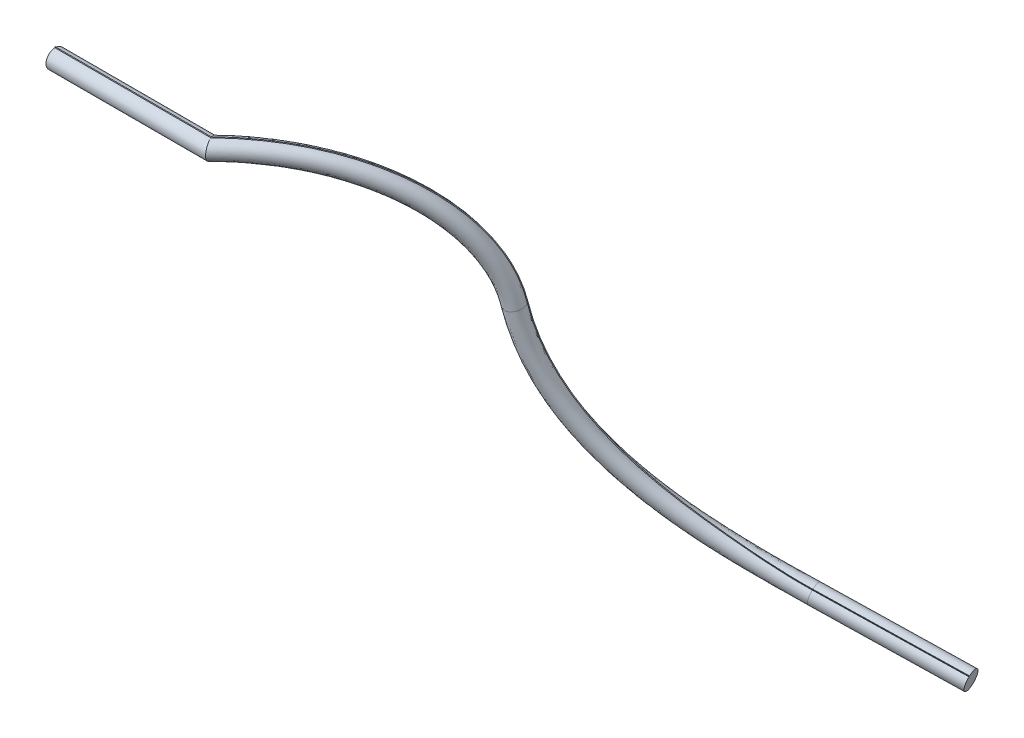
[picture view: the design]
ISO-10303-21;
HEADER;
FILE_DESCRIPTION(('STEP AP214'),'2;1');
FILE_NAME('part.step','',(''),(''),'','','');
FILE_SCHEMA(('AUTOMOTIVE_DESIGN { 1 0 10303 214 1 1 1 1 }'));
ENDSEC;
DATA;
#1=APPLICATION_CONTEXT('core data for automotive mechanical design processes');
#2=APPLICATION_PROTOCOL_DEFINITION('international standard','automotive_design',2000,#1);
#3=PRODUCT_CONTEXT('',#1,'mechanical');
#4=PRODUCT('Part','Part','',(#3));
#5=PRODUCT_RELATED_PRODUCT_CATEGORY('part','',(#4));
#6=PRODUCT_DEFINITION_FORMATION('','',#4);
#7=PRODUCT_DEFINITION_CONTEXT('part definition',#1,'design');
#8=PRODUCT_DEFINITION('design','',#6,#7);
#9=PRODUCT_DEFINITION_SHAPE('','',#8);
#10=(LENGTH_UNIT() NAMED_UNIT(*) SI_UNIT(.MILLI.,.METRE.));
#11=(NAMED_UNIT(*) PLANE_ANGLE_UNIT() SI_UNIT($,.RADIAN.));
#12=(NAMED_UNIT(*) SI_UNIT($,.STERADIAN.) SOLID_ANGLE_UNIT());
#13=UNCERTAINTY_MEASURE_WITH_UNIT(LENGTH_MEASURE(1.E-05),#10,'distance_accuracy_value','');
#14=(GEOMETRIC_REPRESENTATION_CONTEXT(3) GLOBAL_UNCERTAINTY_ASSIGNED_CONTEXT((#13)) GLOBAL_UNIT_ASSIGNED_CONTEXT((#10,
#11,#12)) REPRESENTATION_CONTEXT('',''));
#15=CARTESIAN_POINT('',(0.,0.,0.));
#16=DIRECTION('',(0.,0.,1.));
#17=DIRECTION('',(1.,0.,0.));
#18=AXIS2_PLACEMENT_3D('',#15,#16,#17);
#19=CARTESIAN_POINT('',(68.0766588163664,-45.6233046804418,-41.2127661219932));
#20=DIRECTION('',(0.937856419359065,-0.232670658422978,-0.257467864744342));
#21=DIRECTION('',(-0.264733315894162,0.,-0.964321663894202));
#22=AXIS2_PLACEMENT_3D('',#19,#20,#21);
#23=CYLINDRICAL_SURFACE('',#22,1.25);
#24=CARTESIAN_POINT('',(68.0766588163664,-45.6233046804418,-41.2127661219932));
#25=DIRECTION('',(0.937856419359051,-0.232670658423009,-0.257467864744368));
#26=DIRECTION('',(0.2926105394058,0.131350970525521,0.947167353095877));
#27=AXIS2_PLACEMENT_3D('',#24,#25,#26);
#28=CIRCLE('',#27,1.25);
#29=CARTESIAN_POINT('',(68.5024877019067,-44.6749516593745,-40.5186506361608));
#30=VERTEX_POINT('',#29);
#31=CARTESIAN_POINT('',(68.4945617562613,-44.6174497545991,-40.5994855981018));
#32=VERTEX_POINT('',#31);
#33=EDGE_CURVE('E217',#30,#32,#28,.T.);
#34=ORIENTED_EDGE('',*,*,#33,.T.);
#35=DIRECTION('',(0.937856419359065,-0.232670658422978,-0.257467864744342));
#36=VECTOR('',#35,1.);
#37=CARTESIAN_POINT('',(68.4945617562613,-44.6174497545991,-40.5994855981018));
#38=LINE('',#37,#36);
#39=CARTESIAN_POINT('',(85.0813365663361,-48.732424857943,-45.1530200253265));
#40=VERTEX_POINT('',#39);
#41=EDGE_CURVE('E64',#32,#40,#38,.T.);
#42=ORIENTED_EDGE('',*,*,#41,.T.);
#43=CARTESIAN_POINT('',(84.6634336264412,-49.7382797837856,-45.7663005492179));
#44=DIRECTION('',(0.937856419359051,-0.232670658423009,-0.257467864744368));
#45=DIRECTION('',(0.2926105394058,0.131350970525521,0.947167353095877));
#46=AXIS2_PLACEMENT_3D('',#43,#44,#45);
#47=CIRCLE('',#46,1.25);
#48=CARTESIAN_POINT('',(85.0892625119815,-48.7899267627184,-45.0721850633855));
#49=VERTEX_POINT('',#48);
#50=EDGE_CURVE('E72',#49,#40,#47,.T.);
#51=ORIENTED_EDGE('',*,*,#50,.F.);
#52=DIRECTION('',(0.937856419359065,-0.232670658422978,-0.257467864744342));
#53=VECTOR('',#52,1.);
#54=CARTESIAN_POINT('',(68.5024877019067,-44.6749516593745,-40.5186506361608));
#55=LINE('',#54,#53);
#56=EDGE_CURVE('E12',#30,#49,#55,.T.);
#57=ORIENTED_EDGE('',*,*,#56,.F.);
#58=EDGE_LOOP('',(#34,#42,#51,#57));
#59=FACE_BOUND('',#58,.T.);
#60=ADVANCED_FACE('F51',(#59),#23,.T.);
#61=CARTESIAN_POINT('',(68.5122101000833,-44.595538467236,-40.5550004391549));
#62=DIRECTION('',(0.0894631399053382,0.878961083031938,-0.468426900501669));
#63=DIRECTION('',(0.,0.470312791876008,0.882499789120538));
#64=AXIS2_PLACEMENT_3D('',#61,#62,#63);
#65=PLANE('',#64);
#66=DIRECTION('',(0.335293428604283,0.416283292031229,0.845154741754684));
#67=VECTOR('',#66,1.);
#68=CARTESIAN_POINT('',(68.5122101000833,-44.595538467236,-40.5550004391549));
#69=LINE('',#68,#67);
#70=CARTESIAN_POINT('',(68.5298584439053,-44.5736271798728,-40.5105152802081));
#71=VERTEX_POINT('',#70);
#72=EDGE_CURVE('E155',#32,#71,#69,.T.);
#73=ORIENTED_EDGE('',*,*,#72,.T.);
#74=DIRECTION('',(0.937856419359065,-0.232670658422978,-0.257467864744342));
#75=VECTOR('',#74,1.);
#76=CARTESIAN_POINT('',(68.5298584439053,-44.5736271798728,-40.5105152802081));
#77=LINE('',#76,#75);
#78=CARTESIAN_POINT('',(85.1166332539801,-48.6886022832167,-45.0640497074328));
#79=VERTEX_POINT('',#78);
#80=EDGE_CURVE('E169',#71,#79,#77,.T.);
#81=ORIENTED_EDGE('',*,*,#80,.T.);
#82=DIRECTION('',(0.335293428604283,0.416283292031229,0.845154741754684));
#83=VECTOR('',#82,1.);
#84=CARTESIAN_POINT('',(85.0989849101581,-48.7105135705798,-45.1085348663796));
#85=LINE('',#84,#83);
#86=EDGE_CURVE('E80',#40,#79,#85,.T.);
#87=ORIENTED_EDGE('',*,*,#86,.F.);
#88=ORIENTED_EDGE('',*,*,#41,.F.);
#89=EDGE_LOOP('',(#73,#81,#87,#88));
#90=FACE_BOUND('',#89,.T.);
#91=ADVANCED_FACE('F252',(#90),#65,.T.);
#92=CARTESIAN_POINT('',(68.5161730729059,-44.6242894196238,-40.5145829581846));
#93=DIRECTION('',(0.229834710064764,-0.139419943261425,0.963191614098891));
#94=DIRECTION('',(0.972691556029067,0.,-0.23210156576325));
#95=AXIS2_PLACEMENT_3D('',#92,#93,#94);
#96=PLANE('',#95);
#97=DIRECTION('',(-0.260002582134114,-0.962510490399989,-0.0772800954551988));
#98=VECTOR('',#97,1.);
#99=CARTESIAN_POINT('',(68.5161730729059,-44.6242894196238,-40.5145829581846));
#100=LINE('',#99,#98);
#101=EDGE_CURVE('E220',#71,#30,#100,.T.);
#102=ORIENTED_EDGE('',*,*,#101,.T.);
#103=ORIENTED_EDGE('',*,*,#56,.T.);
#104=DIRECTION('',(-0.260002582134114,-0.962510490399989,-0.0772800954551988));
#105=VECTOR('',#104,1.);
#106=CARTESIAN_POINT('',(85.1029478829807,-48.7392645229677,-45.0681173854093));
#107=LINE('',#106,#105);
#108=EDGE_CURVE('E173',#79,#49,#107,.T.);
#109=ORIENTED_EDGE('',*,*,#108,.F.);
#110=ORIENTED_EDGE('',*,*,#80,.F.);
#111=EDGE_LOOP('',(#102,#103,#109,#110));
#112=FACE_BOUND('',#111,.T.);
#113=ADVANCED_FACE('F224',(#112),#96,.T.);
#114=CARTESIAN_POINT('',(24.6211771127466,1.2490092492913,-6.86904668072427));
#115=DIRECTION('',(0.,-0.472669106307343,-0.881239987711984));
#116=DIRECTION('',(0.,0.881239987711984,-0.472669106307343));
#117=AXIS2_PLACEMENT_3D('',#114,#115,#116);
#118=PLANE('',#117);
#119=DIRECTION('',(0.187943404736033,-0.865536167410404,0.464246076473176));
#120=VECTOR('',#119,1.);
#121=CARTESIAN_POINT('',(21.1667914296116,0.666502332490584,-6.55660849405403));
#122=LINE('',#121,#120);
#123=CARTESIAN_POINT('',(21.0201613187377,1.34177829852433,-6.91880504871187));
#124=VERTEX_POINT('',#123);
#125=CARTESIAN_POINT('',(21.0403052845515,1.2490092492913,-6.86904668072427));
#126=VERTEX_POINT('',#125);
#127=EDGE_CURVE('E176',#124,#126,#122,.T.);
#128=ORIENTED_EDGE('',*,*,#127,.F.);
#129=DIRECTION('',(-1.,0.,0.));
#130=VECTOR('',#129,1.);
#131=CARTESIAN_POINT('',(24.6211771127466,1.34177829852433,-6.91880504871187));
#132=LINE('',#131,#130);
#133=CARTESIAN_POINT('',(0.,1.34177829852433,-6.91880504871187));
#134=VERTEX_POINT('',#133);
#135=EDGE_CURVE('E180',#124,#134,#132,.T.);
#136=ORIENTED_EDGE('',*,*,#135,.T.);
#137=DIRECTION('',(0.,-0.881239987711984,0.472669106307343));
#138=VECTOR('',#137,1.);
#139=CARTESIAN_POINT('',(0.,1.2490092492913,-6.86904668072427));
#140=LINE('',#139,#138);
#141=CARTESIAN_POINT('',(0.,1.2490092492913,-6.86904668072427));
#142=VERTEX_POINT('',#141);
#143=EDGE_CURVE('E184',#134,#142,#140,.T.);
#144=ORIENTED_EDGE('',*,*,#143,.T.);
#145=DIRECTION('',(-1.,0.,0.));
#146=VECTOR('',#145,1.);
#147=CARTESIAN_POINT('',(24.6211771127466,1.2490092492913,-6.86904668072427));
#148=LINE('',#147,#146);
#149=EDGE_CURVE('E182',#126,#142,#148,.T.);
#150=ORIENTED_EDGE('',*,*,#149,.F.);
#151=EDGE_LOOP('',(#128,#136,#144,#150));
#152=FACE_BOUND('',#151,.T.);
#153=ADVANCED_FACE('F231',(#152),#118,.F.);
#154=CARTESIAN_POINT('',(24.6211771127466,1.34177829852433,-6.91880504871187));
#155=DIRECTION('',(0.,-0.472669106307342,0.881239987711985));
#156=DIRECTION('',(0.,-0.881239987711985,-0.472669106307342));
#157=AXIS2_PLACEMENT_3D('',#154,#155,#156);
#158=PLANE('',#157);
#159=DIRECTION('',(0.187943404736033,0.865536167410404,0.464246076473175));
#160=VECTOR('',#159,1.);
#161=CARTESIAN_POINT('',(21.14735900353,1.92756207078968,-6.60460926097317));
#162=LINE('',#161,#160);
#163=CARTESIAN_POINT('',(21.0000173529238,1.2490092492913,-6.96856341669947));
#164=VERTEX_POINT('',#163);
#165=EDGE_CURVE('E179',#164,#124,#162,.T.);
#166=ORIENTED_EDGE('',*,*,#165,.F.);
#167=DIRECTION('',(-1.,0.,0.));
#168=VECTOR('',#167,1.);
#169=CARTESIAN_POINT('',(24.6211771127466,1.2490092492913,-6.96856341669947));
#170=LINE('',#169,#168);
#171=CARTESIAN_POINT('',(0.,1.2490092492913,-6.96856341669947));
#172=VERTEX_POINT('',#171);
#173=EDGE_CURVE('E177',#164,#172,#170,.T.);
#174=ORIENTED_EDGE('',*,*,#173,.T.);
#175=DIRECTION('',(0.,0.881239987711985,0.472669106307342));
#176=VECTOR('',#175,1.);
#177=CARTESIAN_POINT('',(0.,1.34177829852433,-6.91880504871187));
#178=LINE('',#177,#176);
#179=EDGE_CURVE('E187',#172,#134,#178,.T.);
#180=ORIENTED_EDGE('',*,*,#179,.T.);
#181=ORIENTED_EDGE('',*,*,#135,.F.);
#182=EDGE_LOOP('',(#166,#174,#180,#181));
#183=FACE_BOUND('',#182,.T.);
#184=ADVANCED_FACE('F234',(#183),#158,.F.);
#185=CARTESIAN_POINT('',(24.6211771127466,0.,-6.91880504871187));
#186=DIRECTION('',(-1.,0.,0.));
#187=DIRECTION('',(0.,0.,1.));
#188=AXIS2_PLACEMENT_3D('',#185,#186,#187);
#189=CYLINDRICAL_SURFACE('',#188,1.25);
#190=CARTESIAN_POINT('',(21.0201613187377,0.,-6.91880504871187));
#191=DIRECTION('',(0.926923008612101,0.,-0.375251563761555));
#192=DIRECTION('',(-0.375251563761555,0.,-0.926923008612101));
#193=AXIS2_PLACEMENT_3D('',#190,#191,#192);
#194=ELLIPSE('',#193,1.34854781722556,1.25);
#195=EDGE_CURVE('E128',#126,#164,#194,.T.);
#196=ORIENTED_EDGE('',*,*,#195,.F.);
#197=ORIENTED_EDGE('',*,*,#149,.T.);
#198=CARTESIAN_POINT('',(0.,0.,-6.91880504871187));
#199=DIRECTION('',(1.,0.,0.));
#200=DIRECTION('',(0.,0.,-1.));
#201=AXIS2_PLACEMENT_3D('',#198,#199,#200);
#202=CIRCLE('',#201,1.25);
#203=EDGE_CURVE('E190',#142,#172,#202,.T.);
#204=ORIENTED_EDGE('',*,*,#203,.T.);
#205=ORIENTED_EDGE('',*,*,#173,.F.);
#206=EDGE_LOOP('',(#196,#197,#204,#205));
#207=FACE_BOUND('',#206,.T.);
#208=ADVANCED_FACE('F241',(#207),#189,.T.);
#209=CARTESIAN_POINT('',(0.,0.,-6.91880504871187));
#210=DIRECTION('',(1.,0.,0.));
#211=DIRECTION('',(0.,0.,-1.));
#212=AXIS2_PLACEMENT_3D('',#209,#210,#211);
#213=PLANE('',#212);
#214=ORIENTED_EDGE('',*,*,#203,.F.);
#215=ORIENTED_EDGE('',*,*,#143,.F.);
#216=ORIENTED_EDGE('',*,*,#179,.F.);
#217=EDGE_LOOP('',(#214,#215,#216));
#218=FACE_BOUND('',#217,.T.);
#219=ADVANCED_FACE('F239',(#218),#213,.F.);
#220=CARTESIAN_POINT('',(21.0201613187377,1.34177829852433,-6.91880504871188));
#221=CARTESIAN_POINT('',(22.7025609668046,1.34177829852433,-8.54800962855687));
#222=CARTESIAN_POINT('',(26.0569241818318,0.958279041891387,-11.8136614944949));
#223=CARTESIAN_POINT('',(30.9730896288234,-0.80097450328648,-16.5732233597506));
#224=CARTESIAN_POINT('',(34.9737969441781,-3.43791542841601,-20.4272687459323));
#225=CARTESIAN_POINT('',(38.0175675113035,-6.51557415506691,-23.3243306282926));
#226=CARTESIAN_POINT('',(40.2018860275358,-9.58467143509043,-25.3726333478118));
#227=CARTESIAN_POINT('',(41.9527345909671,-13.2240571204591,-26.9549146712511));
#228=CARTESIAN_POINT('',(42.6964716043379,-15.9902305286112,-27.5800700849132));
#229=CARTESIAN_POINT('',(42.943133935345,-17.4066900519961,-27.7463292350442));
#230=CARTESIAN_POINT('',(21.026875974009,1.31085528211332,-6.90221892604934));
#231=CARTESIAN_POINT('',(22.7100324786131,1.31085528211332,-8.53215643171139));
#232=CARTESIAN_POINT('',(26.0663291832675,0.927783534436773,-11.799282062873));
#233=CARTESIAN_POINT('',(30.9771187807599,-0.830018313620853,-16.5533750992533));
#234=CARTESIAN_POINT('',(34.9747901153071,-3.46444486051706,-20.4041277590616));
#235=CARTESIAN_POINT('',(38.0153059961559,-6.53863378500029,-23.2977816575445));
#236=CARTESIAN_POINT('',(40.1969662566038,-9.60350261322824,-25.3432714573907));
#237=CARTESIAN_POINT('',(41.9453177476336,-13.2376482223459,-26.92304623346));
#238=CARTESIAN_POINT('',(42.6879414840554,-15.9976383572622,-27.5467896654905));
#239=CARTESIAN_POINT('',(42.9342675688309,-17.4121669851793,-27.7128221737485));
#240=CARTESIAN_POINT('',(21.0335906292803,1.27993226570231,-6.88563280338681));
#241=CARTESIAN_POINT('',(22.7175039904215,1.27993226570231,-8.51630323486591));
#242=CARTESIAN_POINT('',(26.0757341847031,0.897288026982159,-11.7849026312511));
#243=CARTESIAN_POINT('',(30.9811479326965,-0.859062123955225,-16.533526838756));
#244=CARTESIAN_POINT('',(34.9757832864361,-3.4909742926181,-20.3809867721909));
#245=CARTESIAN_POINT('',(38.0130444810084,-6.56169341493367,-23.2712326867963));
#246=CARTESIAN_POINT('',(40.1920464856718,-9.62233379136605,-25.3139095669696));
#247=CARTESIAN_POINT('',(41.9379009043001,-13.2512393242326,-26.891177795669));
#248=CARTESIAN_POINT('',(42.6794113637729,-16.0050461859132,-27.5135092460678));
#249=CARTESIAN_POINT('',(42.9254012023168,-17.4176439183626,-27.6793151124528));
#250=CARTESIAN_POINT('',(21.0403052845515,1.2490092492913,-6.86904668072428));
#251=CARTESIAN_POINT('',(22.7238069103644,1.2490092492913,-8.49931839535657));
#252=CARTESIAN_POINT('',(26.0856798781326,0.866789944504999,-11.7710466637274));
#253=CARTESIAN_POINT('',(30.9850270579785,-0.888096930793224,-16.5135337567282));
#254=CARTESIAN_POINT('',(34.9768036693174,-3.51753170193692,-20.3578707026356));
#255=CARTESIAN_POINT('',(38.0107680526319,-6.58469435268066,-23.2446722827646));
#256=CARTESIAN_POINT('',(40.1871673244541,-9.64139083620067,-25.2845754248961));
#257=CARTESIAN_POINT('',(41.9303355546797,-13.2639797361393,-26.8592091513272));
#258=CARTESIAN_POINT('',(42.6712013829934,-16.0142924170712,-27.4804446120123));
#259=CARTESIAN_POINT('',(42.9165348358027,-17.4231208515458,-27.645808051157));
#260=B_SPLINE_SURFACE_WITH_KNOTS('',3,3,((#220,#221,#222,#223,#224,#225,#226,#227,#228,#229),
(#230,#231,#232,#233,#234,#235,#236,#237,#238,#239),(#240,#241,#242,#243,#244,#245,#246,#247,
#248,#249),(#250,#251,#252,#253,#254,#255,#256,#257,#258,#259)),.UNSPECIFIED.,.F.,.F.,.F.,(4,4),
(4,1,1,1,1,1,1,4),(0.,0.0514443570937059),(0.,0.184817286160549,0.368761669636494,
0.554454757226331,0.664604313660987,0.775824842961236,0.887744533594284,1.),.UNSPECIFIED.);
#261=CARTESIAN_POINT('',(21.0403052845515,1.2490092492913,-6.86904668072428));
#262=CARTESIAN_POINT('',(22.7238069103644,1.2490092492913,-8.49931839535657));
#263=CARTESIAN_POINT('',(26.0856798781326,0.866789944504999,-11.7710466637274));
#264=CARTESIAN_POINT('',(30.9850270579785,-0.888096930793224,-16.5135337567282));
#265=CARTESIAN_POINT('',(34.9768036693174,-3.51753170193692,-20.3578707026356));
#266=CARTESIAN_POINT('',(38.0107680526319,-6.58469435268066,-23.2446722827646));
#267=CARTESIAN_POINT('',(40.1871673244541,-9.64139083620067,-25.2845754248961));
#268=CARTESIAN_POINT('',(41.9303355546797,-13.2639797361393,-26.8592091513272));
#269=CARTESIAN_POINT('',(42.6712013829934,-16.0142924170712,-27.4804446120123));
#270=CARTESIAN_POINT('',(42.9165348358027,-17.4231208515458,-27.645808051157));
#271=B_SPLINE_CURVE_WITH_KNOTS('',3,(#261,#262,#263,#264,#265,#266,#267,#268,#269,#270),
.UNSPECIFIED.,.F.,.F.,(4,1,1,1,1,1,1,4),(0.,0.184817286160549,0.368761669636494,
0.554454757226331,0.664604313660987,0.775824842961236,0.887744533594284,1.),.UNSPECIFIED.);
#272=CARTESIAN_POINT('',(42.9165348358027,-17.4231208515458,-27.645808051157));
#273=VERTEX_POINT('',#272);
#274=EDGE_CURVE('E151',#126,#273,#271,.T.);
#275=DIRECTION('',(-0.252672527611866,-0.156080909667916,0.954879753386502));
#276=VECTOR('',#275,1.);
#277=CARTESIAN_POINT('',(42.9298343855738,-17.4149054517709,-27.6960686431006));
#278=LINE('',#277,#276);
#279=CARTESIAN_POINT('',(42.943133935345,-17.4066900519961,-27.7463292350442));
#280=VERTEX_POINT('',#279);
#281=EDGE_CURVE('E193',#280,#273,#278,.T.);
#282=CARTESIAN_POINT('',(21.0201613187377,1.34177829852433,-6.91880504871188));
#283=CARTESIAN_POINT('',(22.7025609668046,1.34177829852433,-8.54800962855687));
#284=CARTESIAN_POINT('',(26.0569241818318,0.958279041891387,-11.8136614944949));
#285=CARTESIAN_POINT('',(30.9730896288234,-0.80097450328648,-16.5732233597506));
#286=CARTESIAN_POINT('',(34.9737969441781,-3.43791542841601,-20.4272687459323));
#287=CARTESIAN_POINT('',(38.0175675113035,-6.51557415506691,-23.3243306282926));
#288=CARTESIAN_POINT('',(40.2018860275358,-9.58467143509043,-25.3726333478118));
#289=CARTESIAN_POINT('',(41.9527345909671,-13.2240571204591,-26.9549146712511));
#290=CARTESIAN_POINT('',(42.6964716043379,-15.9902305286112,-27.5800700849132));
#291=CARTESIAN_POINT('',(42.943133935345,-17.4066900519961,-27.7463292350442));
#292=B_SPLINE_CURVE_WITH_KNOTS('',3,(#282,#283,#284,#285,#286,#287,#288,#289,#290,#291),
.UNSPECIFIED.,.F.,.F.,(4,1,1,1,1,1,1,4),(0.,0.184817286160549,0.368761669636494,
0.554454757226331,0.664604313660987,0.775824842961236,0.887744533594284,1.),.UNSPECIFIED.);
#293=EDGE_CURVE('E131',#124,#280,#292,.T.);
#294=ORIENTED_EDGE('',*,*,#127,.T.);
#295=ORIENTED_EDGE('',*,*,#274,.T.);
#296=ORIENTED_EDGE('',*,*,#281,.F.);
#297=ORIENTED_EDGE('',*,*,#293,.F.);
#298=EDGE_LOOP('',(#294,#295,#296,#297));
#299=FACE_BOUND('',#298,.T.);
#300=ADVANCED_FACE('F228',(#299),#260,.T.);
#301=CARTESIAN_POINT('',(21.0403052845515,1.2490092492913,-6.86904668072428));
#302=CARTESIAN_POINT('',(22.7238069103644,1.2490092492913,-8.49931839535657));
#303=CARTESIAN_POINT('',(26.0856798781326,0.866789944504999,-11.7710466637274));
#304=CARTESIAN_POINT('',(30.9850270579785,-0.888096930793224,-16.5135337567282));
#305=CARTESIAN_POINT('',(34.9768036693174,-3.51753170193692,-20.3578707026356));
#306=CARTESIAN_POINT('',(38.0107680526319,-6.58469435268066,-23.2446722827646));
#307=CARTESIAN_POINT('',(40.1871673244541,-9.64139083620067,-25.2845754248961));
#308=CARTESIAN_POINT('',(41.9303355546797,-13.2639797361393,-26.8592091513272));
#309=CARTESIAN_POINT('',(42.6712013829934,-16.0142924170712,-27.4804446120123));
#310=CARTESIAN_POINT('',(42.9165348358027,-17.4231208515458,-27.645808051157));
#311=CARTESIAN_POINT('',(22.0126774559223,1.15332198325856,-4.46715358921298));
#312=CARTESIAN_POINT('',(23.6925890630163,1.15332198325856,-6.09394879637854));
#313=CARTESIAN_POINT('',(28.0695093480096,0.794158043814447,-10.3474685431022));
#314=CARTESIAN_POINT('',(32.5488787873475,-0.941487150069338,-14.6827501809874));
#315=CARTESIAN_POINT('',(36.6381208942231,-3.5443383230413,-18.6209228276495));
#316=CARTESIAN_POINT('',(39.6531055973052,-6.58465082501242,-21.4892922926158));
#317=CARTESIAN_POINT('',(41.835449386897,-9.61951897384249,-23.5349039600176));
#318=CARTESIAN_POINT('',(43.5747682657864,-13.2001175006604,-25.1070141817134));
#319=CARTESIAN_POINT('',(44.3416265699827,-15.9605522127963,-25.752391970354));
#320=CARTESIAN_POINT('',(44.5812368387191,-17.3365152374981,-25.9138977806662));
#321=CARTESIAN_POINT('',(21.9933048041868,-1.25,-4.51500670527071));
#322=CARTESIAN_POINT('',(23.5807840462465,-1.25,-6.05229212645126));
#323=CARTESIAN_POINT('',(27.7601784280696,-1.58835182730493,-10.0835096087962));
#324=CARTESIAN_POINT('',(31.9599751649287,-3.21932242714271,-14.1274590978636));
#325=CARTESIAN_POINT('',(35.7752170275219,-5.63821340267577,-17.7725321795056));
#326=CARTESIAN_POINT('',(38.5384281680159,-8.41623451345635,-20.3768470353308));
#327=CARTESIAN_POINT('',(40.5079244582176,-11.1333022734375,-22.1970952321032));
#328=CARTESIAN_POINT('',(42.0468886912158,-14.2991364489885,-23.5686088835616));
#329=CARTESIAN_POINT('',(42.7201720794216,-16.6177443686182,-24.0945784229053));
#330=CARTESIAN_POINT('',(42.9297205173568,-17.8210771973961,-24.2358214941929));
#331=CARTESIAN_POINT('',(20.0470178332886,-1.25,-9.32260339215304));
#332=CARTESIAN_POINT('',(21.6173209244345,-1.25,-10.843255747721));
#333=CARTESIAN_POINT('',(23.7757576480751,-1.63287811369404,-12.9172643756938));
#334=CARTESIAN_POINT('',(28.7831743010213,-3.29366955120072,-17.7426881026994));
#335=CARTESIAN_POINT('',(32.3843329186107,-5.75212472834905,-21.1792787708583));
#336=CARTESIAN_POINT('',(35.1646350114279,-8.56050957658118,-23.7987630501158));
#337=CARTESIAN_POINT('',(37.1067812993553,-11.303973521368,-25.5906771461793));
#338=CARTESIAN_POINT('',(38.6321656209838,-14.4903222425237,-26.9476685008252));
#339=CARTESIAN_POINT('',(39.2592583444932,-16.8295359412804,-27.4247745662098));
#340=CARTESIAN_POINT('',(39.4688076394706,-18.0328736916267,-27.5660182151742));
#341=CARTESIAN_POINT('',(20.027645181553,1.15332198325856,-9.37045650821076));
#342=CARTESIAN_POINT('',(21.6732044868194,1.15332198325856,-10.9639855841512));
#343=CARTESIAN_POINT('',(24.0135520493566,0.748745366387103,-13.2451721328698));
#344=CARTESIAN_POINT('',(29.3066977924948,-1.01731434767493,-18.3678775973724));
#345=CARTESIAN_POINT('',(33.1800552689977,-3.66051724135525,-22.0958001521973));
#346=CARTESIAN_POINT('',(36.2120817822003,-6.73179816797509,-24.9792639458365));
#347=CARTESIAN_POINT('',(38.3666169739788,-9.79358723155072,-26.9960606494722));
#348=CARTESIAN_POINT('',(40.0920624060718,-13.3951115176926,-28.5533368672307));
#349=CARTESIAN_POINT('',(40.8118145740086,-16.1765551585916,-29.1488827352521));
#350=CARTESIAN_POINT('',(41.0514265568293,-17.5525280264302,-29.3103897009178));
#351=CARTESIAN_POINT('',(21.0000173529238,1.2490092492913,-6.96856341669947));
#352=CARTESIAN_POINT('',(22.6739047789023,1.2490092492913,-8.58952491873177));
#353=CARTESIAN_POINT('',(26.0074830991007,0.865868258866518,-11.8338500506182));
#354=CARTESIAN_POINT('',(30.9180913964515,-0.889635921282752,-16.5872295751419));
#355=CARTESIAN_POINT('',(34.906789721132,-3.51988961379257,-20.4285613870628));
#356=CARTESIAN_POINT('',(37.9408937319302,-6.58768091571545,-23.3154695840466));
#357=CARTESIAN_POINT('',(40.1167740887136,-9.64492338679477,-25.3548319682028));
#358=CARTESIAN_POINT('',(41.8596484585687,-13.267938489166,-26.9291526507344));
#359=CARTESIAN_POINT('',(42.5995603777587,-16.0186738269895,-27.5493790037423));
#360=CARTESIAN_POINT('',(42.8448943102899,-17.4275050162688,-27.7147427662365));
#361=(BOUNDED_SURFACE() B_SPLINE_SURFACE(3,3,((#301,#302,#303,#304,#305,#306,#307,#308,#309,
#310),(#311,#312,#313,#314,#315,#316,#317,#318,#319,#320),(#321,#322,#323,#324,#325,#326,#327,
#328,#329,#330),(#331,#332,#333,#334,#335,#336,#337,#338,#339,#340),(#341,#342,#343,#344,#345,
#346,#347,#348,#349,#350),(#351,#352,#353,#354,#355,#356,#357,#358,#359,#360)),.UNSPECIFIED.,
.F.,.F.,.F.) B_SPLINE_SURFACE_WITH_KNOTS((4,2,4),(4,1,1,1,1,1,1,4),(0.0514443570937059,0.5,
0.948555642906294),(0.,0.184817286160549,0.368761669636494,0.554454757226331,0.664604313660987,
0.775824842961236,0.887744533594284,1.),
.UNSPECIFIED.) GEOMETRIC_REPRESENTATION_ITEM() RATIONAL_B_SPLINE_SURFACE(((1.,1.,1.,1.,1.,1.,1.,
1.,1.,1.),(0.120134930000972,0.120134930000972,0.120134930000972,0.120134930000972,
0.120134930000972,0.120134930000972,0.120134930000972,0.120134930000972,0.120134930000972,
0.120134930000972),(0.0416393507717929,0.0416393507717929,0.0416393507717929,0.0416393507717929,
0.0416393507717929,0.0416393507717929,0.0416393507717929,0.0416393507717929,0.0416393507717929,
0.0416393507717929),(0.0416393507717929,0.0416393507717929,0.0416393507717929,
0.0416393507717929,0.0416393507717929,0.0416393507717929,0.0416393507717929,0.0416393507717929,
0.0416393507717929,0.0416393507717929),(0.120134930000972,0.120134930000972,0.120134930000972,
0.120134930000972,0.120134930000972,0.120134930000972,0.120134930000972,0.120134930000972,
0.120134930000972,0.120134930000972),(1.,1.,1.,1.,1.,1.,1.,1.,1.,1.))) REPRESENTATION_ITEM('') SURFACE());
#362=CARTESIAN_POINT('',(21.0000173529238,1.2490092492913,-6.96856341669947));
#363=CARTESIAN_POINT('',(22.6739047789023,1.2490092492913,-8.58952491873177));
#364=CARTESIAN_POINT('',(26.0074830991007,0.865868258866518,-11.8338500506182));
#365=CARTESIAN_POINT('',(30.9180913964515,-0.889635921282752,-16.5872295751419));
#366=CARTESIAN_POINT('',(34.906789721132,-3.51988961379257,-20.4285613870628));
#367=CARTESIAN_POINT('',(37.9408937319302,-6.58768091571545,-23.3154695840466));
#368=CARTESIAN_POINT('',(40.1167740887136,-9.64492338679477,-25.3548319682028));
#369=CARTESIAN_POINT('',(41.8596484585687,-13.267938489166,-26.9291526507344));
#370=CARTESIAN_POINT('',(42.5995603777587,-16.0186738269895,-27.5493790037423));
#371=CARTESIAN_POINT('',(42.8448943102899,-17.4275050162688,-27.7147427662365));
#372=B_SPLINE_CURVE_WITH_KNOTS('',3,(#362,#363,#364,#365,#366,#367,#368,#369,#370,#371),
.UNSPECIFIED.,.F.,.F.,(4,1,1,1,1,1,1,4),(0.,0.184817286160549,0.368761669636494,
0.554454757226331,0.664604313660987,0.775824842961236,0.887744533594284,1.),.UNSPECIFIED.);
#373=CARTESIAN_POINT('',(42.8448943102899,-17.4275050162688,-27.7147427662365));
#374=VERTEX_POINT('',#373);
#375=EDGE_CURVE('E120',#164,#374,#372,.T.);
#376=CARTESIAN_POINT('',(42.0403226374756,-17.6760447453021,-26.7909503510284));
#377=DIRECTION('',(0.170422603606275,-0.97865255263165,-0.114870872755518));
#378=DIRECTION('',(0.985173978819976,0.171558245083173,0.));
#379=AXIS2_PLACEMENT_3D('',#376,#377,#378);
#380=CIRCLE('',#379,1.25);
#381=EDGE_CURVE('E125',#273,#374,#380,.T.);
#382=ORIENTED_EDGE('',*,*,#195,.T.);
#383=ORIENTED_EDGE('',*,*,#375,.T.);
#384=ORIENTED_EDGE('',*,*,#381,.F.);
#385=ORIENTED_EDGE('',*,*,#274,.F.);
#386=EDGE_LOOP('',(#382,#383,#384,#385));
#387=FACE_BOUND('',#386,.T.);
#388=ADVANCED_FACE('F122',(#387),#361,.T.);
#389=CARTESIAN_POINT('',(21.0000173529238,1.2490092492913,-6.96856341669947));
#390=CARTESIAN_POINT('',(22.6739047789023,1.2490092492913,-8.58952491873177));
#391=CARTESIAN_POINT('',(26.0074830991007,0.865868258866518,-11.8338500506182));
#392=CARTESIAN_POINT('',(30.9180913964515,-0.889635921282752,-16.5872295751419));
#393=CARTESIAN_POINT('',(34.906789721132,-3.51988961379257,-20.4285613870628));
#394=CARTESIAN_POINT('',(37.9408937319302,-6.58768091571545,-23.3154695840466));
#395=CARTESIAN_POINT('',(40.1167740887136,-9.64492338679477,-25.3548319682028));
#396=CARTESIAN_POINT('',(41.8596484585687,-13.267938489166,-26.9291526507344));
#397=CARTESIAN_POINT('',(42.5995603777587,-16.0186738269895,-27.5493790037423));
#398=CARTESIAN_POINT('',(42.8448943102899,-17.4275050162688,-27.7147427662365));
#399=CARTESIAN_POINT('',(21.0067320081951,1.27993226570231,-6.95197729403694));
#400=CARTESIAN_POINT('',(22.6838683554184,1.27993226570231,-8.57608499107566));
#401=CARTESIAN_POINT('',(26.0237729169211,0.896673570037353,-11.8269361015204));
#402=CARTESIAN_POINT('',(30.936477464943,-0.860088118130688,-16.5826121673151));
#403=CARTESIAN_POINT('',(34.9291143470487,-3.49254623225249,-20.4281206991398));
#404=CARTESIAN_POINT('',(37.966460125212,-6.56368446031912,-23.3184294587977));
#405=CARTESIAN_POINT('',(40.1451180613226,-9.62468881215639,-25.3607476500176));
#406=CARTESIAN_POINT('',(41.8907760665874,-13.2538785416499,-26.9378066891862));
#407=CARTESIAN_POINT('',(42.6316506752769,-16.0079670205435,-27.5594654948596));
#408=CARTESIAN_POINT('',(42.8776408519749,-17.4205666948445,-27.7252715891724));
#409=CARTESIAN_POINT('',(21.0134466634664,1.31085528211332,-6.93539117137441));
#410=CARTESIAN_POINT('',(22.6932146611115,1.31085528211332,-8.56204730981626));
#411=CARTESIAN_POINT('',(26.0403485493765,0.92747630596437,-11.8202987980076));
#412=CARTESIAN_POINT('',(30.9547835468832,-0.830531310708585,-16.5779177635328));
#413=CARTESIAN_POINT('',(34.9514556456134,-3.46523083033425,-20.427694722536));
#414=CARTESIAN_POINT('',(37.9920138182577,-6.53962930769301,-23.3213800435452));
#415=CARTESIAN_POINT('',(40.1735020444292,-9.60468012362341,-25.3666904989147));
#416=CARTESIAN_POINT('',(41.9217553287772,-13.2389678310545,-26.9463606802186));
#417=CARTESIAN_POINT('',(42.6640611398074,-15.9990987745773,-27.5697677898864));
#418=CARTESIAN_POINT('',(42.91038739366,-17.4136283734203,-27.7358004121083));
#419=CARTESIAN_POINT('',(21.0201613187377,1.34177829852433,-6.91880504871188));
#420=CARTESIAN_POINT('',(22.7025609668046,1.34177829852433,-8.54800962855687));
#421=CARTESIAN_POINT('',(26.0569241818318,0.958279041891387,-11.8136614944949));
#422=CARTESIAN_POINT('',(30.9730896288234,-0.80097450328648,-16.5732233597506));
#423=CARTESIAN_POINT('',(34.9737969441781,-3.43791542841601,-20.4272687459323));
#424=CARTESIAN_POINT('',(38.0175675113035,-6.51557415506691,-23.3243306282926));
#425=CARTESIAN_POINT('',(40.2018860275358,-9.58467143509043,-25.3726333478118));
#426=CARTESIAN_POINT('',(41.9527345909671,-13.2240571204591,-26.9549146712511));
#427=CARTESIAN_POINT('',(42.6964716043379,-15.9902305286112,-27.5800700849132));
#428=CARTESIAN_POINT('',(42.943133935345,-17.4066900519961,-27.7463292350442));
#429=B_SPLINE_SURFACE_WITH_KNOTS('',3,3,((#389,#390,#391,#392,#393,#394,#395,#396,#397,#398),
(#399,#400,#401,#402,#403,#404,#405,#406,#407,#408),(#409,#410,#411,#412,#413,#414,#415,#416,
#417,#418),(#419,#420,#421,#422,#423,#424,#425,#426,#427,#428)),.UNSPECIFIED.,.F.,.F.,.F.,(4,4),
(4,1,1,1,1,1,1,4),(0.948555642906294,1.),(0.,0.184817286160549,0.368761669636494,
0.554454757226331,0.664604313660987,0.775824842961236,0.887744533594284,1.),.UNSPECIFIED.);
#430=DIRECTION('',(0.933206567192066,0.197727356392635,-0.300048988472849));
#431=VECTOR('',#430,1.);
#432=CARTESIAN_POINT('',(42.8940141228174,-17.4170975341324,-27.7305360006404));
#433=LINE('',#432,#431);
#434=EDGE_CURVE('E134',#374,#280,#433,.T.);
#435=ORIENTED_EDGE('',*,*,#165,.T.);
#436=ORIENTED_EDGE('',*,*,#293,.T.);
#437=ORIENTED_EDGE('',*,*,#434,.F.);
#438=ORIENTED_EDGE('',*,*,#375,.F.);
#439=EDGE_LOOP('',(#435,#436,#437,#438));
#440=FACE_BOUND('',#439,.T.);
#441=ADVANCED_FACE('F135',(#440),#429,.T.);
#442=CARTESIAN_POINT('',(84.2412330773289,-50.7161588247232,-46.4205170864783));
#443=DIRECTION('',(-0.937856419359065,0.232670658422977,0.257467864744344));
#444=DIRECTION('',(-0.292610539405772,-0.131350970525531,-0.947167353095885));
#445=AXIS2_PLACEMENT_3D('',#442,#443,#444);
#446=PLANE('',#445);
#447=ORIENTED_EDGE('',*,*,#108,.T.);
#448=ORIENTED_EDGE('',*,*,#50,.T.);
#449=ORIENTED_EDGE('',*,*,#86,.T.);
#450=EDGE_LOOP('',(#447,#448,#449));
#451=FACE_BOUND('',#450,.T.);
#452=ADVANCED_FACE('F261',(#451),#446,.F.);
#453=CARTESIAN_POINT('',(42.8448943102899,-17.4275050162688,-27.7147427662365));
#454=CARTESIAN_POINT('',(43.2873461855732,-19.9682868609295,-28.0129710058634));
#455=CARTESIAN_POINT('',(44.2973765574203,-23.2368966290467,-28.682958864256));
#456=CARTESIAN_POINT('',(45.7259938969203,-26.2309724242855,-29.6412649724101));
#457=CARTESIAN_POINT('',(46.8662104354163,-28.4057189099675,-30.4013978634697));
#458=CARTESIAN_POINT('',(47.7258276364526,-29.7900990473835,-30.9682862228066));
#459=CARTESIAN_POINT('',(48.6838432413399,-31.1071226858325,-31.5754811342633));
#460=CARTESIAN_POINT('',(49.6559609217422,-32.4407978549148,-32.1913146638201));
#461=CARTESIAN_POINT('',(50.7141930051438,-33.6868229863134,-32.8393190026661));
#462=CARTESIAN_POINT('',(52.3779065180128,-35.3887842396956,-33.8105674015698));
#463=CARTESIAN_POINT('',(53.5369739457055,-36.4976580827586,-34.4731939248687));
#464=CARTESIAN_POINT('',(54.7698546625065,-37.5241346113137,-35.142449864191));
#465=CARTESIAN_POINT('',(56.7006367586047,-39.0248507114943,-36.1556499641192));
#466=CARTESIAN_POINT('',(58.0527472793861,-39.9422104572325,-36.8223845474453));
#467=CARTESIAN_POINT('',(59.7866353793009,-40.9731147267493,-37.5892913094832));
#468=CARTESIAN_POINT('',(62.6039382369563,-42.5971961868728,-38.805152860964));
#469=CARTESIAN_POINT('',(65.6029482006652,-43.9000759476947,-39.8056566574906));
#470=CARTESIAN_POINT('',(68.4945617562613,-44.6174497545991,-40.5994855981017));
#471=CARTESIAN_POINT('',(42.8776408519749,-17.4205666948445,-27.7252715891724));
#472=CARTESIAN_POINT('',(43.3193395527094,-19.9570234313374,-28.022992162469));
#473=CARTESIAN_POINT('',(44.328794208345,-23.2231733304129,-28.6911694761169));
#474=CARTESIAN_POINT('',(45.7563413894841,-26.2144748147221,-29.647316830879));
#475=CARTESIAN_POINT('',(46.89570641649,-28.3871987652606,-30.4057256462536));
#476=CARTESIAN_POINT('',(47.7546849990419,-29.770288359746,-30.9713131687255));
#477=CARTESIAN_POINT('',(48.7120983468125,-31.0863652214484,-31.5769396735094));
#478=CARTESIAN_POINT('',(49.683606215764,-32.4190856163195,-32.1911802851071));
#479=CARTESIAN_POINT('',(50.7412717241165,-33.6645109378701,-32.8373462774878));
#480=CARTESIAN_POINT('',(52.4040713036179,-35.3659397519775,-33.8056108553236));
#481=CARTESIAN_POINT('',(53.5624967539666,-36.4745690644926,-34.4661359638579));
#482=CARTESIAN_POINT('',(54.7946431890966,-37.5009919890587,-35.133155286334));
#483=CARTESIAN_POINT('',(56.7242129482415,-39.0018921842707,-36.142866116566));
#484=CARTESIAN_POINT('',(58.0754041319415,-39.9197090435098,-36.807191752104));
#485=CARTESIAN_POINT('',(59.8079310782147,-40.9519427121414,-37.5710228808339));
#486=CARTESIAN_POINT('',(62.6229529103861,-42.5784635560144,-38.7818894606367));
#487=CARTESIAN_POINT('',(65.6189140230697,-43.8865104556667,-39.7771529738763));
#488=CARTESIAN_POINT('',(68.5063273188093,-44.6028422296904,-40.5698288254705));
#489=CARTESIAN_POINT('',(42.91038739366,-17.4136283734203,-27.7358004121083));
#490=CARTESIAN_POINT('',(43.3517074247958,-19.9479105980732,-28.0332657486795));
#491=CARTESIAN_POINT('',(44.3602084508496,-23.2094897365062,-28.6993821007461));
#492=CARTESIAN_POINT('',(45.7866480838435,-26.197702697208,-29.6533382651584));
#493=CARTESIAN_POINT('',(46.9251644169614,-28.3683618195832,-30.4100206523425));
#494=CARTESIAN_POINT('',(47.7835463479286,-29.7503833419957,-30.9743342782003));
#495=CARTESIAN_POINT('',(48.7403533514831,-31.0656103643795,-31.5783983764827));
#496=CARTESIAN_POINT('',(49.7112466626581,-32.3974725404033,-32.1910518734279));
#497=CARTESIAN_POINT('',(50.7682961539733,-33.6422693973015,-32.8353647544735));
#498=CARTESIAN_POINT('',(52.4301862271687,-35.3431168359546,-33.8006430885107));
#499=CARTESIAN_POINT('',(53.5879978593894,-36.4514664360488,-34.4590714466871));
#500=CARTESIAN_POINT('',(54.8195372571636,-37.4778535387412,-35.123888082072));
#501=CARTESIAN_POINT('',(56.7480668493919,-38.9789734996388,-36.1301563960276));
#502=CARTESIAN_POINT('',(58.0984250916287,-39.897281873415,-36.7920977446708));
#503=CARTESIAN_POINT('',(59.8293643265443,-40.9308009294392,-37.5527919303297));
#504=CARTESIAN_POINT('',(62.6416105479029,-42.5596566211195,-38.7585290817));
#505=CARTESIAN_POINT('',(65.6327192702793,-43.87240895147,-39.7480561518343));
#506=CARTESIAN_POINT('',(68.5180928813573,-44.5882347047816,-40.5401720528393));
#507=CARTESIAN_POINT('',(42.943133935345,-17.4066900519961,-27.7463292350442));
#508=CARTESIAN_POINT('',(43.3840752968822,-19.9387977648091,-28.0435393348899));
#509=CARTESIAN_POINT('',(44.3916226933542,-23.1958061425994,-28.7075947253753));
#510=CARTESIAN_POINT('',(45.8169547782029,-26.1809305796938,-29.6593596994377));
#511=CARTESIAN_POINT('',(46.9546224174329,-28.3495248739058,-30.4143156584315));
#512=CARTESIAN_POINT('',(47.8124076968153,-29.7304783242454,-30.9773553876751));
#513=CARTESIAN_POINT('',(48.7686083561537,-31.0448555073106,-31.5798570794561));
#514=CARTESIAN_POINT('',(49.7388871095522,-32.3758594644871,-32.1909234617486));
#515=CARTESIAN_POINT('',(50.79532058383,-33.6200278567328,-32.8333832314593));
#516=CARTESIAN_POINT('',(52.4563011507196,-35.3202939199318,-33.7956753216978));
#517=CARTESIAN_POINT('',(53.6134989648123,-36.4283638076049,-34.4520069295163));
#518=CARTESIAN_POINT('',(54.8444313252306,-37.4547150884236,-35.11462087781));
#519=CARTESIAN_POINT('',(56.7719207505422,-38.956054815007,-36.1174466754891));
#520=CARTESIAN_POINT('',(58.1214460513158,-39.8748547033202,-36.7770037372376));
#521=CARTESIAN_POINT('',(59.850797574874,-40.9096591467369,-37.5345609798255));
#522=CARTESIAN_POINT('',(62.6602681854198,-42.5408496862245,-38.7351687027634));
#523=CARTESIAN_POINT('',(65.6465245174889,-43.8583074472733,-39.7189593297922));
#524=CARTESIAN_POINT('',(68.5298584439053,-44.5736271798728,-40.510515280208));
#525=B_SPLINE_SURFACE_WITH_KNOTS('',3,3,((#453,#454,#455,#456,#457,#458,#459,#460,#461,#462,
#463,#464,#465,#466,#467,#468,#469,#470),(#471,#472,#473,#474,#475,#476,#477,#478,#479,#480,
#481,#482,#483,#484,#485,#486,#487,#488),(#489,#490,#491,#492,#493,#494,#495,#496,#497,#498,
#499,#500,#501,#502,#503,#504,#505,#506),(#507,#508,#509,#510,#511,#512,#513,#514,#515,#516,
#517,#518,#519,#520,#521,#522,#523,#524)),.UNSPECIFIED.,.F.,.F.,.F.,(4,4),(4,1,2,1,2,2,1,2,2,1,
4),(0.94582657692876,1.),(0.,0.186666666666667,0.25,0.373333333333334,0.375,0.5,0.56,0.625,0.75,
0.78,1.),.UNSPECIFIED.);
#526=CARTESIAN_POINT('',(42.943133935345,-17.4066900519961,-27.7463292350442));
#527=CARTESIAN_POINT('',(43.3840752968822,-19.9387977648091,-28.0435393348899));
#528=CARTESIAN_POINT('',(44.3916226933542,-23.1958061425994,-28.7075947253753));
#529=CARTESIAN_POINT('',(45.8169547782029,-26.1809305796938,-29.6593596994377));
#530=CARTESIAN_POINT('',(46.9546224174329,-28.3495248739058,-30.4143156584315));
#531=CARTESIAN_POINT('',(47.8124076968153,-29.7304783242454,-30.9773553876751));
#532=CARTESIAN_POINT('',(48.7686083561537,-31.0448555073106,-31.5798570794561));
#533=CARTESIAN_POINT('',(49.7388871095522,-32.3758594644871,-32.1909234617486));
#534=CARTESIAN_POINT('',(50.79532058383,-33.6200278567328,-32.8333832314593));
#535=CARTESIAN_POINT('',(52.4563011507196,-35.3202939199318,-33.7956753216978));
#536=CARTESIAN_POINT('',(53.6134989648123,-36.4283638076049,-34.4520069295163));
#537=CARTESIAN_POINT('',(54.8444313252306,-37.4547150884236,-35.11462087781));
#538=CARTESIAN_POINT('',(56.7719207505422,-38.956054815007,-36.1174466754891));
#539=CARTESIAN_POINT('',(58.1214460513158,-39.8748547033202,-36.7770037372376));
#540=CARTESIAN_POINT('',(59.850797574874,-40.9096591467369,-37.5345609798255));
#541=CARTESIAN_POINT('',(62.6602681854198,-42.5408496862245,-38.7351687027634));
#542=CARTESIAN_POINT('',(65.6465245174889,-43.8583074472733,-39.7189593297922));
#543=CARTESIAN_POINT('',(68.5298584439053,-44.5736271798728,-40.510515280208));
#544=B_SPLINE_CURVE_WITH_KNOTS('',3,(#526,#527,#528,#529,#530,#531,#532,#533,#534,#535,#536,
#537,#538,#539,#540,#541,#542,#543),.UNSPECIFIED.,.F.,.F.,(4,1,2,1,2,2,1,2,2,1,4),(0.,
0.186666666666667,0.25,0.373333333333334,0.375,0.5,0.56,0.625,0.75,0.78,1.),.UNSPECIFIED.);
#545=EDGE_CURVE('E141',#280,#71,#544,.T.);
#546=CARTESIAN_POINT('',(42.8448943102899,-17.4275050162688,-27.7147427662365));
#547=CARTESIAN_POINT('',(43.2873461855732,-19.9682868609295,-28.0129710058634));
#548=CARTESIAN_POINT('',(44.2973765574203,-23.2368966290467,-28.682958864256));
#549=CARTESIAN_POINT('',(45.7259938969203,-26.2309724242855,-29.6412649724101));
#550=CARTESIAN_POINT('',(46.8662104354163,-28.4057189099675,-30.4013978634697));
#551=CARTESIAN_POINT('',(47.7258276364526,-29.7900990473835,-30.9682862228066));
#552=CARTESIAN_POINT('',(48.6838432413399,-31.1071226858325,-31.5754811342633));
#553=CARTESIAN_POINT('',(49.6559609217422,-32.4407978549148,-32.1913146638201));
#554=CARTESIAN_POINT('',(50.7141930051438,-33.6868229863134,-32.8393190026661));
#555=CARTESIAN_POINT('',(52.3779065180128,-35.3887842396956,-33.8105674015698));
#556=CARTESIAN_POINT('',(53.5369739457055,-36.4976580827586,-34.4731939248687));
#557=CARTESIAN_POINT('',(54.7698546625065,-37.5241346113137,-35.142449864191));
#558=CARTESIAN_POINT('',(56.7006367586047,-39.0248507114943,-36.1556499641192));
#559=CARTESIAN_POINT('',(58.0527472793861,-39.9422104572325,-36.8223845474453));
#560=CARTESIAN_POINT('',(59.7866353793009,-40.9731147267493,-37.5892913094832));
#561=CARTESIAN_POINT('',(62.6039382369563,-42.5971961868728,-38.805152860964));
#562=CARTESIAN_POINT('',(65.6029482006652,-43.9000759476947,-39.8056566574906));
#563=CARTESIAN_POINT('',(68.4945617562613,-44.6174497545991,-40.5994855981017));
#564=B_SPLINE_CURVE_WITH_KNOTS('',3,(#546,#547,#548,#549,#550,#551,#552,#553,#554,#555,#556,
#557,#558,#559,#560,#561,#562,#563),.UNSPECIFIED.,.F.,.F.,(4,1,2,1,2,2,1,2,2,1,4),(0.,
0.186666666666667,0.25,0.373333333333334,0.375,0.5,0.56,0.625,0.75,0.78,1.),.UNSPECIFIED.);
#565=EDGE_CURVE('E148',#374,#32,#564,.T.);
#566=ORIENTED_EDGE('',*,*,#434,.T.);
#567=ORIENTED_EDGE('',*,*,#545,.T.);
#568=ORIENTED_EDGE('',*,*,#72,.F.);
#569=ORIENTED_EDGE('',*,*,#565,.F.);
#570=EDGE_LOOP('',(#566,#567,#568,#569));
#571=FACE_BOUND('',#570,.T.);
#572=ADVANCED_FACE('F153',(#571),#525,.T.);
#573=CARTESIAN_POINT('',(42.9165348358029,-17.4231208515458,-27.6458080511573));
#574=CARTESIAN_POINT('',(43.3587586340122,-19.9625929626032,-27.9438825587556));
#575=CARTESIAN_POINT('',(44.3659783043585,-23.2302901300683,-28.6111545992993));
#576=CARTESIAN_POINT('',(45.7917501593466,-26.2244889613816,-29.5667905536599));
#577=CARTESIAN_POINT('',(46.9297138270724,-28.3996539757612,-30.3248859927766));
#578=CARTESIAN_POINT('',(47.787655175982,-29.7847403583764,-30.8903529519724));
#579=CARTESIAN_POINT('',(48.7435123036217,-31.1032385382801,-31.4959338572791));
#580=CARTESIAN_POINT('',(49.7134362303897,-32.4384182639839,-32.1101292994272));
#581=CARTESIAN_POINT('',(50.7690225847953,-33.6866945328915,-32.7563275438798));
#582=CARTESIAN_POINT('',(52.4283068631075,-35.3929087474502,-33.7249603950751));
#583=CARTESIAN_POINT('',(53.5842150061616,-36.5049550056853,-34.3858382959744));
#584=CARTESIAN_POINT('',(54.8136536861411,-37.5351573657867,-35.0534940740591));
#585=CARTESIAN_POINT('',(56.7389447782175,-39.0420986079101,-36.0647167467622));
#586=CARTESIAN_POINT('',(58.0871149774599,-39.9642647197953,-36.7307258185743));
#587=CARTESIAN_POINT('',(59.8156031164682,-41.0023858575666,-37.4984646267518));
#588=CARTESIAN_POINT('',(62.6239974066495,-42.6385939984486,-38.7163385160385));
#589=CARTESIAN_POINT('',(65.6123576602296,-43.9579458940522,-39.7252289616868));
#590=CARTESIAN_POINT('',(68.5024877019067,-44.6749516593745,-40.5186506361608));
#591=CARTESIAN_POINT('',(44.5812368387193,-17.336515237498,-25.9138977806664));
#592=CARTESIAN_POINT('',(45.029109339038,-19.9084250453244,-26.2157797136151));
#593=CARTESIAN_POINT('',(45.9597862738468,-23.1108404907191,-26.8157235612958));
#594=CARTESIAN_POINT('',(47.3178571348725,-26.1091621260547,-27.7114492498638));
#595=CARTESIAN_POINT('',(48.4030014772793,-28.2998968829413,-28.4246016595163));
#596=CARTESIAN_POINT('',(49.2226135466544,-29.7116987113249,-28.9596989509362));
#597=CARTESIAN_POINT('',(50.1269971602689,-31.0717825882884,-29.5304806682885));
#598=CARTESIAN_POINT('',(51.0445847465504,-32.4493033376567,-30.109354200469));
#599=CARTESIAN_POINT('',(52.0354591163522,-33.754229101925,-30.7163482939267));
#600=CARTESIAN_POINT('',(53.5885094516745,-35.5657682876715,-31.6296848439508));
#601=CARTESIAN_POINT('',(54.6692454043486,-36.7559477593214,-32.2540844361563));
#602=CARTESIAN_POINT('',(55.8193225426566,-37.8786315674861,-32.8900743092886));
#603=CARTESIAN_POINT('',(57.6173545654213,-39.5393720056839,-33.8645298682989));
#604=CARTESIAN_POINT('',(58.8734141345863,-40.5794568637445,-34.5207289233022));
#605=CARTESIAN_POINT('',(60.4672734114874,-41.7902403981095,-35.3169454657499));
#606=CARTESIAN_POINT('',(63.0506230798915,-43.7151723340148,-36.596483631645));
#607=CARTESIAN_POINT('',(65.7403440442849,-45.4129549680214,-37.8158032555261));
#608=CARTESIAN_POINT('',(68.6614655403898,-46.1376493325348,-38.6177329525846));
#609=CARTESIAN_POINT('',(42.929720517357,-17.821077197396,-24.2358214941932));
#610=CARTESIAN_POINT('',(43.4095441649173,-20.5764666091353,-24.559239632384));
#611=CARTESIAN_POINT('',(44.373803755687,-24.0924774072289,-25.2818827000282));
#612=CARTESIAN_POINT('',(45.7820313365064,-27.3278961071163,-26.314167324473));
#613=CARTESIAN_POINT('',(46.9051387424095,-29.6837376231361,-27.136068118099));
#614=CARTESIAN_POINT('',(47.7508411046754,-31.1905503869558,-27.752835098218));
#615=CARTESIAN_POINT('',(48.675243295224,-32.6364320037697,-28.424967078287));
#616=CARTESIAN_POINT('',(49.6130348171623,-34.1007697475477,-29.1068070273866));
#617=CARTESIAN_POINT('',(50.6178110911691,-35.4821396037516,-29.8350126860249));
#618=CARTESIAN_POINT('',(52.1864460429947,-37.3912258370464,-30.9478032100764));
#619=CARTESIAN_POINT('',(53.2760936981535,-38.6422591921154,-31.7134752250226));
#620=CARTESIAN_POINT('',(54.4329897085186,-39.8146373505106,-32.5013903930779));
#621=CARTESIAN_POINT('',(56.2468431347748,-41.5366991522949,-33.7196776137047));
#622=CARTESIAN_POINT('',(57.5202152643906,-42.5991436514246,-34.5526196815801));
#623=CARTESIAN_POINT('',(59.1655561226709,-43.7990815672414,-35.6017752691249));
#624=CARTESIAN_POINT('',(61.843558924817,-45.6915896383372,-37.3023548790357));
#625=CARTESIAN_POINT('',(64.7413614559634,-47.2199261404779,-39.0621524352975));
#626=CARTESIAN_POINT('',(67.8459072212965,-47.9901258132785,-39.9144372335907));
#627=CARTESIAN_POINT('',(39.4688076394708,-18.0328736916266,-27.5660182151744));
#628=CARTESIAN_POINT('',(39.9490201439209,-20.7904961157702,-27.8896984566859));
#629=CARTESIAN_POINT('',(41.0598283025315,-24.410516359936,-28.7506593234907));
#630=CARTESIAN_POINT('',(42.6065153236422,-27.6488931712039,-29.9128402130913));
#631=CARTESIAN_POINT('',(43.8383391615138,-29.985706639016,-30.8332253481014));
#632=CARTESIAN_POINT('',(44.7637976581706,-31.4520837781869,-31.5178913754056));
#633=CARTESIAN_POINT('',(45.7926699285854,-32.8239994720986,-32.2678465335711));
#634=CARTESIAN_POINT('',(46.8366566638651,-34.2129326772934,-33.0286792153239));
#635=CARTESIAN_POINT('',(47.9708179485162,-35.4864063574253,-33.8446014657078));
#636=CARTESIAN_POINT('',(49.7532520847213,-37.1914112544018,-35.0838029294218));
#637=CARTESIAN_POINT('',(50.9945941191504,-38.2901534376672,-35.9337819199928));
#638=CARTESIAN_POINT('',(52.3136920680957,-39.2819176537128,-36.7979080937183));
#639=CARTESIAN_POINT('',(54.3872986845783,-40.7020783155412,-38.110224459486));
#640=CARTESIAN_POINT('',(55.8482693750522,-41.5312782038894,-38.9774321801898));
#641=CARTESIAN_POINT('',(57.7617371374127,-42.3840278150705,-39.9883594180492));
#642=CARTESIAN_POINT('',(60.885946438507,-43.6941166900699,-41.5960348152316));
#643=CARTESIAN_POINT('',(64.3559342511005,-44.4414144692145,-42.9665489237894));
#644=CARTESIAN_POINT('',(67.463009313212,-45.2122416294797,-43.8195280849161));
#645=CARTESIAN_POINT('',(41.0514265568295,-17.5525280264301,-29.310389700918));
#646=CARTESIAN_POINT('',(41.5000767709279,-20.1289038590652,-29.6127958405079));
#647=CARTESIAN_POINT('',(42.5798336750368,-23.4352507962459,-30.3535557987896));
#648=CARTESIAN_POINT('',(44.0790846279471,-26.4362702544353,-31.3817312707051));
#649=CARTESIAN_POINT('',(45.2751138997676,-28.6075554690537,-32.1953265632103));
#650=CARTESIAN_POINT('',(46.176112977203,-29.978343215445,-32.7997021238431));
#651=CARTESIAN_POINT('',(47.1870393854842,-31.2630866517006,-33.4498615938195));
#652=CARTESIAN_POINT('',(48.2129284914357,-32.5637992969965,-34.1093054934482));
#653=CARTESIAN_POINT('',(49.3357072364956,-33.7586503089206,-34.805745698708));
#654=CARTESIAN_POINT('',(51.1068191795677,-35.3619960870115,-35.8480077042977));
#655=CARTESIAN_POINT('',(52.3423026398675,-36.3968180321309,-36.5583986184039));
#656=CARTESIAN_POINT('',(53.6579570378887,-37.3353146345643,-37.272155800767));
#657=CARTESIAN_POINT('',(55.7211109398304,-38.6881857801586,-38.3425661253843));
#658=CARTESIAN_POINT('',(57.1686024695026,-39.4904204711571,-39.0337410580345));
#659=CARTESIAN_POINT('',(59.0356661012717,-40.347051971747,-39.7908976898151));
#660=CARTESIAN_POINT('',(62.0735371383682,-41.6778479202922,-40.9755276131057));
#661=CARTESIAN_POINT('',(65.3447650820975,-42.5785156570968,-41.7972451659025));
#662=CARTESIAN_POINT('',(68.2709451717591,-43.3044649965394,-42.600563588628));
#663=CARTESIAN_POINT('',(42.8448943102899,-17.4275050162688,-27.7147427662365));
#664=CARTESIAN_POINT('',(43.2873461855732,-19.9682868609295,-28.0129710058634));
#665=CARTESIAN_POINT('',(44.2973765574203,-23.2368966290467,-28.682958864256));
#666=CARTESIAN_POINT('',(45.7259938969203,-26.2309724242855,-29.6412649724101));
#667=CARTESIAN_POINT('',(46.8662104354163,-28.4057189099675,-30.4013978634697));
#668=CARTESIAN_POINT('',(47.7258276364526,-29.7900990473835,-30.9682862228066));
#669=CARTESIAN_POINT('',(48.6838432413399,-31.1071226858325,-31.5754811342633));
#670=CARTESIAN_POINT('',(49.6559609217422,-32.4407978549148,-32.1913146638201));
#671=CARTESIAN_POINT('',(50.7141930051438,-33.6868229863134,-32.8393190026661));
#672=CARTESIAN_POINT('',(52.3779065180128,-35.3887842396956,-33.8105674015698));
#673=CARTESIAN_POINT('',(53.5369739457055,-36.4976580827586,-34.4731939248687));
#674=CARTESIAN_POINT('',(54.7698546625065,-37.5241346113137,-35.142449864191));
#675=CARTESIAN_POINT('',(56.7006367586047,-39.0248507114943,-36.1556499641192));
#676=CARTESIAN_POINT('',(58.0527472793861,-39.9422104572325,-36.8223845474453));
#677=CARTESIAN_POINT('',(59.7866353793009,-40.9731147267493,-37.5892913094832));
#678=CARTESIAN_POINT('',(62.6039382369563,-42.5971961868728,-38.805152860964));
#679=CARTESIAN_POINT('',(65.6029482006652,-43.9000759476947,-39.8056566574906));
#680=CARTESIAN_POINT('',(68.4945617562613,-44.6174497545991,-40.5994855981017));
#681=(BOUNDED_SURFACE() B_SPLINE_SURFACE(3,3,((#573,#574,#575,#576,#577,#578,#579,#580,#581,
#582,#583,#584,#585,#586,#587,#588,#589,#590),(#591,#592,#593,#594,#595,#596,#597,#598,#599,
#600,#601,#602,#603,#604,#605,#606,#607,#608),(#609,#610,#611,#612,#613,#614,#615,#616,#617,
#618,#619,#620,#621,#622,#623,#624,#625,#626),(#627,#628,#629,#630,#631,#632,#633,#634,#635,
#636,#637,#638,#639,#640,#641,#642,#643,#644),(#645,#646,#647,#648,#649,#650,#651,#652,#653,
#654,#655,#656,#657,#658,#659,#660,#661,#662),(#663,#664,#665,#666,#667,#668,#669,#670,#671,
#672,#673,#674,#675,#676,#677,#678,#679,#680)),.UNSPECIFIED.,.F.,.F.,
.F.) B_SPLINE_SURFACE_WITH_KNOTS((4,2,4),(4,1,2,1,2,2,1,2,2,1,4),(0.0541734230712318,
0.499999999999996,0.94582657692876),(0.,0.186666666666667,0.25,0.373333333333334,0.375,0.5,0.56,
0.625,0.75,0.78,1.),
.UNSPECIFIED.) GEOMETRIC_REPRESENTATION_ITEM() RATIONAL_B_SPLINE_SURFACE(((1.,1.,1.,1.,1.,1.,1.,
1.,1.,1.,1.,1.,1.,1.,1.,1.,1.,1.),(0.120134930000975,0.120134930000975,0.120134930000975,
0.120134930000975,0.120134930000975,0.120134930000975,0.120134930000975,0.120134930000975,
0.120134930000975,0.120134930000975,0.120134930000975,0.120134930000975,0.120134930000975,
0.120134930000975,0.120134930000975,0.120134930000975,0.120134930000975,0.120134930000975),
(0.0416393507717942,0.0416393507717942,0.0416393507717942,0.0416393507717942,0.0416393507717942,
0.0416393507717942,0.0416393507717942,0.0416393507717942,0.0416393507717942,0.0416393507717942,
0.0416393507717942,0.0416393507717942,0.0416393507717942,0.0416393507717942,0.0416393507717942,
0.0416393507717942,0.0416393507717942,0.0416393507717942),(0.0416393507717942,
0.0416393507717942,0.0416393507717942,0.0416393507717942,0.0416393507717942,0.0416393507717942,
0.0416393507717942,0.0416393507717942,0.0416393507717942,0.0416393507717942,0.0416393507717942,
0.0416393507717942,0.0416393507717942,0.0416393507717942,0.0416393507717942,0.0416393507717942,
0.0416393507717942,0.0416393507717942),(0.120134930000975,0.120134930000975,0.120134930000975,
0.120134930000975,0.120134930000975,0.120134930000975,0.120134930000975,0.120134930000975,
0.120134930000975,0.120134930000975,0.120134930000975,0.120134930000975,0.120134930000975,
0.120134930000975,0.120134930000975,0.120134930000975,0.120134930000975,0.120134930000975),(1.,
1.,1.,1.,1.,1.,1.,1.,1.,1.,1.,1.,1.,1.,1.,1.,1.,1.))) REPRESENTATION_ITEM('') SURFACE());
#682=CARTESIAN_POINT('',(42.9165348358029,-17.4231208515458,-27.6458080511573));
#683=CARTESIAN_POINT('',(43.3587586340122,-19.9625929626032,-27.9438825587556));
#684=CARTESIAN_POINT('',(44.3659783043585,-23.2302901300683,-28.6111545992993));
#685=CARTESIAN_POINT('',(45.7917501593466,-26.2244889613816,-29.5667905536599));
#686=CARTESIAN_POINT('',(46.9297138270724,-28.3996539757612,-30.3248859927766));
#687=CARTESIAN_POINT('',(47.787655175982,-29.7847403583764,-30.8903529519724));
#688=CARTESIAN_POINT('',(48.7435123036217,-31.1032385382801,-31.4959338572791));
#689=CARTESIAN_POINT('',(49.7134362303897,-32.4384182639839,-32.1101292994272));
#690=CARTESIAN_POINT('',(50.7690225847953,-33.6866945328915,-32.7563275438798));
#691=CARTESIAN_POINT('',(52.4283068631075,-35.3929087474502,-33.7249603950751));
#692=CARTESIAN_POINT('',(53.5842150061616,-36.5049550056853,-34.3858382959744));
#693=CARTESIAN_POINT('',(54.8136536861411,-37.5351573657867,-35.0534940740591));
#694=CARTESIAN_POINT('',(56.7389447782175,-39.0420986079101,-36.0647167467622));
#695=CARTESIAN_POINT('',(58.0871149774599,-39.9642647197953,-36.7307258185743));
#696=CARTESIAN_POINT('',(59.8156031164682,-41.0023858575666,-37.4984646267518));
#697=CARTESIAN_POINT('',(62.6239974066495,-42.6385939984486,-38.7163385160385));
#698=CARTESIAN_POINT('',(65.6123576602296,-43.9579458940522,-39.7252289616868));
#699=CARTESIAN_POINT('',(68.5024877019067,-44.6749516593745,-40.5186506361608));
#700=B_SPLINE_CURVE_WITH_KNOTS('',3,(#682,#683,#684,#685,#686,#687,#688,#689,#690,#691,#692,
#693,#694,#695,#696,#697,#698,#699),.UNSPECIFIED.,.F.,.F.,(4,1,2,1,2,2,1,2,2,1,4),(0.,
0.186666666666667,0.25,0.373333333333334,0.375,0.5,0.56,0.625,0.75,0.78,1.),.UNSPECIFIED.);
#701=EDGE_CURVE('E57',#273,#30,#700,.T.);
#702=ORIENTED_EDGE('',*,*,#381,.T.);
#703=ORIENTED_EDGE('',*,*,#565,.T.);
#704=ORIENTED_EDGE('',*,*,#33,.F.);
#705=ORIENTED_EDGE('',*,*,#701,.F.);
#706=EDGE_LOOP('',(#702,#703,#704,#705));
#707=FACE_BOUND('',#706,.T.);
#708=ADVANCED_FACE('F146',(#707),#681,.T.);
#709=CARTESIAN_POINT('',(42.943133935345,-17.4066900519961,-27.7463292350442));
#710=CARTESIAN_POINT('',(43.3840752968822,-19.9387977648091,-28.0435393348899));
#711=CARTESIAN_POINT('',(44.3916226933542,-23.1958061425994,-28.7075947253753));
#712=CARTESIAN_POINT('',(45.8169547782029,-26.1809305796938,-29.6593596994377));
#713=CARTESIAN_POINT('',(46.9546224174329,-28.3495248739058,-30.4143156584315));
#714=CARTESIAN_POINT('',(47.8124076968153,-29.7304783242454,-30.9773553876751));
#715=CARTESIAN_POINT('',(48.7686083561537,-31.0448555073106,-31.5798570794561));
#716=CARTESIAN_POINT('',(49.7388871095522,-32.3758594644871,-32.1909234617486));
#717=CARTESIAN_POINT('',(50.79532058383,-33.6200278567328,-32.8333832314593));
#718=CARTESIAN_POINT('',(52.4563011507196,-35.3202939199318,-33.7956753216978));
#719=CARTESIAN_POINT('',(53.6134989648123,-36.4283638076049,-34.4520069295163));
#720=CARTESIAN_POINT('',(54.8444313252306,-37.4547150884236,-35.11462087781));
#721=CARTESIAN_POINT('',(56.7719207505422,-38.956054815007,-36.1174466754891));
#722=CARTESIAN_POINT('',(58.1214460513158,-39.8748547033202,-36.7770037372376));
#723=CARTESIAN_POINT('',(59.850797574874,-40.9096591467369,-37.5345609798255));
#724=CARTESIAN_POINT('',(62.6602681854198,-42.5408496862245,-38.7351687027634));
#725=CARTESIAN_POINT('',(65.6465245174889,-43.8583074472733,-39.7189593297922));
#726=CARTESIAN_POINT('',(68.5298584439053,-44.5736271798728,-40.510515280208));
#727=CARTESIAN_POINT('',(42.9342675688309,-17.4121669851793,-27.7128221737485));
#728=CARTESIAN_POINT('',(43.3755069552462,-19.945986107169,-28.0102331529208));
#729=CARTESIAN_POINT('',(44.3830757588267,-23.2072870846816,-28.6754473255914));
#730=CARTESIAN_POINT('',(45.8085673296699,-26.1955449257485,-29.6285138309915));
#731=CARTESIAN_POINT('',(46.9463326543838,-28.3663440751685,-30.3845170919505));
#732=CARTESIAN_POINT('',(47.8041554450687,-29.7485982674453,-30.9483565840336));
#733=CARTESIAN_POINT('',(48.7602430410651,-31.0643156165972,-31.5518826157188));
#734=CARTESIAN_POINT('',(49.7304051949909,-32.3966781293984,-32.163990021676));
#735=CARTESIAN_POINT('',(50.7865734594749,-33.6422257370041,-32.8077010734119));
#736=CARTESIAN_POINT('',(52.4469870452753,-35.3444914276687,-33.7721075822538));
#737=CARTESIAN_POINT('',(53.60374517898,-36.4538989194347,-34.4299529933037));
#738=CARTESIAN_POINT('',(54.834135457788,-37.4815276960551,-35.0942357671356));
#739=CARTESIAN_POINT('',(56.760832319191,-38.9847221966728,-36.099844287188));
#740=CARTESIAN_POINT('',(58.1098759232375,-39.9046322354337,-36.7615434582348));
#741=CARTESIAN_POINT('',(59.8390183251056,-40.9405575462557,-37.5225158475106));
#742=CARTESIAN_POINT('',(62.6483019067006,-42.5734569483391,-38.7289256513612));
#743=CARTESIAN_POINT('',(65.6358858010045,-43.8917063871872,-39.7212551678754));
#744=CARTESIAN_POINT('',(68.5207348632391,-44.6074020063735,-40.5132270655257));
#745=CARTESIAN_POINT('',(42.9254012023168,-17.4176439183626,-27.6793151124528));
#746=CARTESIAN_POINT('',(43.3669386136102,-19.9531744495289,-27.9769269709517));
#747=CARTESIAN_POINT('',(44.3745288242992,-23.2187680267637,-28.6432999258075));
#748=CARTESIAN_POINT('',(45.8001798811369,-26.2101592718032,-29.5976679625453));
#749=CARTESIAN_POINT('',(46.9380428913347,-28.3831632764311,-30.3547185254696));
#750=CARTESIAN_POINT('',(47.7959031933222,-29.7667182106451,-30.919357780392));
#751=CARTESIAN_POINT('',(48.7518777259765,-31.0837757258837,-31.5239081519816));
#752=CARTESIAN_POINT('',(49.7219232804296,-32.4174967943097,-32.1370565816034));
#753=CARTESIAN_POINT('',(50.7778263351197,-33.6644236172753,-32.7820189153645));
#754=CARTESIAN_POINT('',(52.4376729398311,-35.3686889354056,-33.7485398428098));
#755=CARTESIAN_POINT('',(53.5939913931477,-36.4794340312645,-34.407899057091));
#756=CARTESIAN_POINT('',(54.8238395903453,-37.5083403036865,-35.0738506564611));
#757=CARTESIAN_POINT('',(56.7497438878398,-39.0133895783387,-36.0822418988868));
#758=CARTESIAN_POINT('',(58.0983057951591,-39.9344097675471,-36.746083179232));
#759=CARTESIAN_POINT('',(59.8272390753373,-40.9714559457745,-37.5104707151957));
#760=CARTESIAN_POINT('',(62.6363356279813,-42.6060642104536,-38.7226825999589));
#761=CARTESIAN_POINT('',(65.6252470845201,-43.925105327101,-39.7235510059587));
#762=CARTESIAN_POINT('',(68.5116112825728,-44.6411768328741,-40.5159388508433));
#763=CARTESIAN_POINT('',(42.9165348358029,-17.4231208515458,-27.6458080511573));
#764=CARTESIAN_POINT('',(43.3587586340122,-19.9625929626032,-27.9438825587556));
#765=CARTESIAN_POINT('',(44.3659783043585,-23.2302901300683,-28.6111545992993));
#766=CARTESIAN_POINT('',(45.7917501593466,-26.2244889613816,-29.5667905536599));
#767=CARTESIAN_POINT('',(46.9297138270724,-28.3996539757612,-30.3248859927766));
#768=CARTESIAN_POINT('',(47.787655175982,-29.7847403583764,-30.8903529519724));
#769=CARTESIAN_POINT('',(48.7435123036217,-31.1032385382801,-31.4959338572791));
#770=CARTESIAN_POINT('',(49.7134362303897,-32.4384182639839,-32.1101292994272));
#771=CARTESIAN_POINT('',(50.7690225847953,-33.6866945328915,-32.7563275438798));
#772=CARTESIAN_POINT('',(52.4283068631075,-35.3929087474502,-33.7249603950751));
#773=CARTESIAN_POINT('',(53.5842150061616,-36.5049550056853,-34.3858382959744));
#774=CARTESIAN_POINT('',(54.8136536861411,-37.5351573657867,-35.0534940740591));
#775=CARTESIAN_POINT('',(56.7389447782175,-39.0420986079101,-36.0647167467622));
#776=CARTESIAN_POINT('',(58.0871149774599,-39.9642647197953,-36.7307258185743));
#777=CARTESIAN_POINT('',(59.8156031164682,-41.0023858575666,-37.4984646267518));
#778=CARTESIAN_POINT('',(62.6239974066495,-42.6385939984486,-38.7163385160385));
#779=CARTESIAN_POINT('',(65.6123576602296,-43.9579458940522,-39.7252289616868));
#780=CARTESIAN_POINT('',(68.5024877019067,-44.6749516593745,-40.5186506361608));
#781=B_SPLINE_SURFACE_WITH_KNOTS('',3,3,((#709,#710,#711,#712,#713,#714,#715,#716,#717,#718,
#719,#720,#721,#722,#723,#724,#725,#726),(#727,#728,#729,#730,#731,#732,#733,#734,#735,#736,
#737,#738,#739,#740,#741,#742,#743,#744),(#745,#746,#747,#748,#749,#750,#751,#752,#753,#754,
#755,#756,#757,#758,#759,#760,#761,#762),(#763,#764,#765,#766,#767,#768,#769,#770,#771,#772,
#773,#774,#775,#776,#777,#778,#779,#780)),.UNSPECIFIED.,.F.,.F.,.F.,(4,4),(4,1,2,1,2,2,1,2,2,1,
4),(0.,0.0541734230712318),(0.,0.186666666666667,0.25,0.373333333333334,0.375,0.5,0.56,0.625,
0.75,0.78,1.),.UNSPECIFIED.);
#782=ORIENTED_EDGE('',*,*,#281,.T.);
#783=ORIENTED_EDGE('',*,*,#701,.T.);
#784=ORIENTED_EDGE('',*,*,#101,.F.);
#785=ORIENTED_EDGE('',*,*,#545,.F.);
#786=EDGE_LOOP('',(#782,#783,#784,#785));
#787=FACE_BOUND('',#786,.T.);
#788=ADVANCED_FACE('F53',(#787),#781,.T.);
#789=CLOSED_SHELL('',(#60,#91,#113,#153,#184,#208,#219,#300,#388,#441,#452,#572,#708,#788));
#790=MANIFOLD_SOLID_BREP('B2',#789);
#791=ADVANCED_BREP_SHAPE_REPRESENTATION('',(#18,#790),#14);
#792=SHAPE_DEFINITION_REPRESENTATION(#9,#791);
ENDSEC;
END-ISO-10303-21;
